VERSION 5.4 ;
NAMESCASESENSITIVE ON ;
BUSBITCHARS "[]" ;
DIVIDERCHAR "/" ;
UNITS
  DATABASE MICRONS 2000 ;
END UNITS
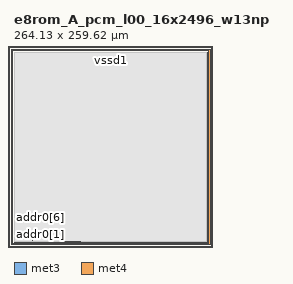
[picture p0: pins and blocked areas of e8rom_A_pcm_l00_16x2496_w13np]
MACRO e8rom_A_pcm_l00_16x2496_w13np
   CLASS BLOCK ;
   SIZE 264.13 BY 259.62 ;
   SYMMETRY X Y R90 ;
   PIN clk0
      DIRECTION INPUT ;
      PORT
         LAYER met3 ;
         RECT  4.31 8.935 4.8 9.425 ;
      END
   END clk0
   PIN cs0
      DIRECTION INPUT ;
      PORT
         LAYER met3 ;
         RECT  25.31 2.5 25.8 2.99 ;
      END
   END cs0
   PIN addr0[0]
      DIRECTION INPUT ;
      PORT
         LAYER met3 ;
         RECT  32.175 1.39 32.665 1.88 ;
      END
   END addr0[0]
   PIN addr0[1]
      DIRECTION INPUT ;
      PORT
         LAYER met3 ;
         RECT  34.215 1.39 34.705 1.88 ;
      END
   END addr0[1]
   PIN addr0[2]
      DIRECTION INPUT ;
      PORT
         LAYER met3 ;
         RECT  36.255 1.39 36.745 1.88 ;
      END
   END addr0[2]
   PIN addr0[3]
      DIRECTION INPUT ;
      PORT
         LAYER met3 ;
         RECT  38.295 1.39 38.785 1.88 ;
      END
   END addr0[3]
   PIN addr0[4]
      DIRECTION INPUT ;
      PORT
         LAYER met3 ;
         RECT  1.525 33.835 2.015 34.325 ;
      END
   END addr0[4]
   PIN addr0[5]
      DIRECTION INPUT ;
      PORT
         LAYER met3 ;
         RECT  3.565 33.835 4.055 34.325 ;
      END
   END addr0[5]
   PIN addr0[6]
      DIRECTION INPUT ;
      PORT
         LAYER met3 ;
         RECT  5.605 33.835 6.095 34.325 ;
      END
   END addr0[6]
   PIN addr0[7]
      DIRECTION INPUT ;
      PORT
         LAYER met3 ;
         RECT  7.645 33.835 8.135 34.325 ;
      END
   END addr0[7]
   PIN addr0[8]
      DIRECTION INPUT ;
      PORT
         LAYER met3 ;
         RECT  9.685 33.835 10.175 34.325 ;
      END
   END addr0[8]
   PIN addr0[9]
      DIRECTION INPUT ;
      PORT
         LAYER met3 ;
         RECT  11.725 33.835 12.215 34.325 ;
      END
   END addr0[9]
   PIN addr0[10]
      DIRECTION INPUT ;
      PORT
         LAYER met3 ;
         RECT  13.765 33.835 14.255 34.325 ;
      END
   END addr0[10]
   PIN addr0[11]
      DIRECTION INPUT ;
      PORT
         LAYER met3 ;
         RECT  15.805 33.835 16.295 34.325 ;
      END
   END addr0[11]
   PIN dout0[0]
      DIRECTION OUTPUT ;
      PORT
         LAYER met3 ;
         RECT  67.18 -0.16 67.67 0.33 ;
      END
   END dout0[0]
   PIN dout0[1]
      DIRECTION OUTPUT ;
      PORT
         LAYER met3 ;
         RECT  68.72 -0.16 69.21 0.33 ;
      END
   END dout0[1]
   PIN dout0[2]
      DIRECTION OUTPUT ;
      PORT
         LAYER met3 ;
         RECT  70.26 -0.16 70.75 0.33 ;
      END
   END dout0[2]
   PIN dout0[3]
      DIRECTION OUTPUT ;
      PORT
         LAYER met3 ;
         RECT  71.8 -0.16 72.29 0.33 ;
      END
   END dout0[3]
   PIN dout0[4]
      DIRECTION OUTPUT ;
      PORT
         LAYER met3 ;
         RECT  73.34 -0.16 73.83 0.33 ;
      END
   END dout0[4]
   PIN dout0[5]
      DIRECTION OUTPUT ;
      PORT
         LAYER met3 ;
         RECT  74.88 -0.16 75.37 0.33 ;
      END
   END dout0[5]
   PIN dout0[6]
      DIRECTION OUTPUT ;
      PORT
         LAYER met3 ;
         RECT  76.42 -0.16 76.91 0.33 ;
      END
   END dout0[6]
   PIN dout0[7]
      DIRECTION OUTPUT ;
      PORT
         LAYER met3 ;
         RECT  77.96 -0.16 78.45 0.33 ;
      END
   END dout0[7]
   PIN dout0[8]
      DIRECTION OUTPUT ;
      PORT
         LAYER met3 ;
         RECT  79.5 -0.16 79.99 0.33 ;
      END
   END dout0[8]
   PIN dout0[9]
      DIRECTION OUTPUT ;
      PORT
         LAYER met3 ;
         RECT  81.04 -0.16 81.53 0.33 ;
      END
   END dout0[9]
   PIN dout0[10]
      DIRECTION OUTPUT ;
      PORT
         LAYER met3 ;
         RECT  82.58 -0.16 83.07 0.33 ;
      END
   END dout0[10]
   PIN dout0[11]
      DIRECTION OUTPUT ;
      PORT
         LAYER met3 ;
         RECT  84.12 -0.16 84.61 0.33 ;
      END
   END dout0[11]
   PIN dout0[12]
      DIRECTION OUTPUT ;
      PORT
         LAYER met3 ;
         RECT  85.66 -0.16 86.15 0.33 ;
      END
   END dout0[12]
   PIN dout0[13]
      DIRECTION OUTPUT ;
      PORT
         LAYER met3 ;
         RECT  87.2 -0.16 87.69 0.33 ;
      END
   END dout0[13]
   PIN dout0[14]
      DIRECTION OUTPUT ;
      PORT
         LAYER met3 ;
         RECT  88.74 -0.16 89.23 0.33 ;
      END
   END dout0[14]
   PIN dout0[15]
      DIRECTION OUTPUT ;
      PORT
         LAYER met3 ;
         RECT  90.28 -0.16 90.77 0.33 ;
      END
   END dout0[15]
   PIN vccd1
      DIRECTION INOUT ;
      USE POWER ; 
      SHAPE ABUTMENT ; 
      PORT
         LAYER met3 ;
         RECT  -7.48 -7.48 271.61 -5.74 ;
         LAYER met4 ;
         RECT  -7.48 -7.48 -5.74 267.1 ;
         LAYER met4 ;
         RECT  269.87 -7.48 271.61 267.1 ;
         LAYER met3 ;
         RECT  -7.48 265.36 271.61 267.1 ;
      END
   END vccd1
   PIN vssd1
      DIRECTION INOUT ;
      USE GROUND ; 
      SHAPE ABUTMENT ; 
      PORT
         LAYER met4 ;
         RECT  266.39 -4.0 268.13 263.62 ;
         LAYER met3 ;
         RECT  -4.0 261.88 268.13 263.62 ;
         LAYER met3 ;
         RECT  -4.0 -4.0 268.13 -2.26 ;
         LAYER met4 ;
         RECT  -4.0 -4.0 -2.26 263.62 ;
      END
   END vssd1
   OBS
   LAYER  met1 ;
      RECT  0.62 0.62 263.51 259.0 ;
   LAYER  met2 ;
      RECT  0.62 0.62 263.51 259.0 ;
   LAYER  met3 ;
      RECT  0.62 0.62 3.71 8.335 ;
      RECT  0.62 8.335 3.71 10.025 ;
      RECT  3.71 0.62 5.4 8.335 ;
      RECT  5.4 8.335 263.51 10.025 ;
      RECT  5.4 0.62 24.71 1.9 ;
      RECT  5.4 1.9 24.71 3.59 ;
      RECT  5.4 3.59 24.71 8.335 ;
      RECT  24.71 0.62 26.4 1.9 ;
      RECT  24.71 3.59 26.4 8.335 ;
      RECT  26.4 3.59 263.51 8.335 ;
      RECT  26.4 0.62 31.575 0.79 ;
      RECT  26.4 0.79 31.575 1.9 ;
      RECT  31.575 0.62 33.265 0.79 ;
      RECT  26.4 1.9 31.575 2.48 ;
      RECT  26.4 2.48 31.575 3.59 ;
      RECT  31.575 2.48 33.265 3.59 ;
      RECT  33.265 2.48 263.51 3.59 ;
      RECT  33.265 0.79 33.615 1.9 ;
      RECT  33.265 1.9 33.615 2.48 ;
      RECT  35.305 0.79 35.655 1.9 ;
      RECT  35.305 1.9 35.655 2.48 ;
      RECT  37.345 0.79 37.695 1.9 ;
      RECT  37.345 1.9 37.695 2.48 ;
      RECT  39.385 1.9 263.51 2.48 ;
      RECT  0.62 10.025 0.925 33.235 ;
      RECT  0.62 33.235 0.925 34.925 ;
      RECT  0.62 34.925 0.925 259.0 ;
      RECT  0.925 10.025 2.615 33.235 ;
      RECT  0.925 34.925 2.615 259.0 ;
      RECT  2.615 10.025 3.71 33.235 ;
      RECT  2.615 34.925 3.71 259.0 ;
      RECT  3.71 10.025 4.655 33.235 ;
      RECT  3.71 34.925 4.655 259.0 ;
      RECT  4.655 10.025 5.4 33.235 ;
      RECT  4.655 34.925 5.4 259.0 ;
      RECT  2.615 33.235 2.965 34.925 ;
      RECT  5.4 10.025 6.695 33.235 ;
      RECT  5.4 34.925 6.695 259.0 ;
      RECT  6.695 10.025 263.51 33.235 ;
      RECT  6.695 34.925 263.51 259.0 ;
      RECT  4.655 33.235 5.005 34.925 ;
      RECT  6.695 33.235 7.045 34.925 ;
      RECT  8.735 33.235 9.085 34.925 ;
      RECT  10.775 33.235 11.125 34.925 ;
      RECT  12.815 33.235 13.165 34.925 ;
      RECT  14.855 33.235 15.205 34.925 ;
      RECT  16.895 33.235 263.51 34.925 ;
      RECT  33.265 0.62 66.58 0.79 ;
      RECT  39.385 0.79 66.58 0.93 ;
      RECT  39.385 0.93 66.58 1.9 ;
      RECT  66.58 0.93 68.27 1.9 ;
      RECT  68.27 0.93 263.51 1.9 ;
      RECT  91.37 0.62 263.51 0.79 ;
      RECT  91.37 0.79 263.51 0.93 ;
   LAYER  met4 ;
      RECT  0.62 0.62 263.51 259.0 ;
   END
END    e8rom_A_pcm_l00_16x2496_w13np
END    LIBRARY
